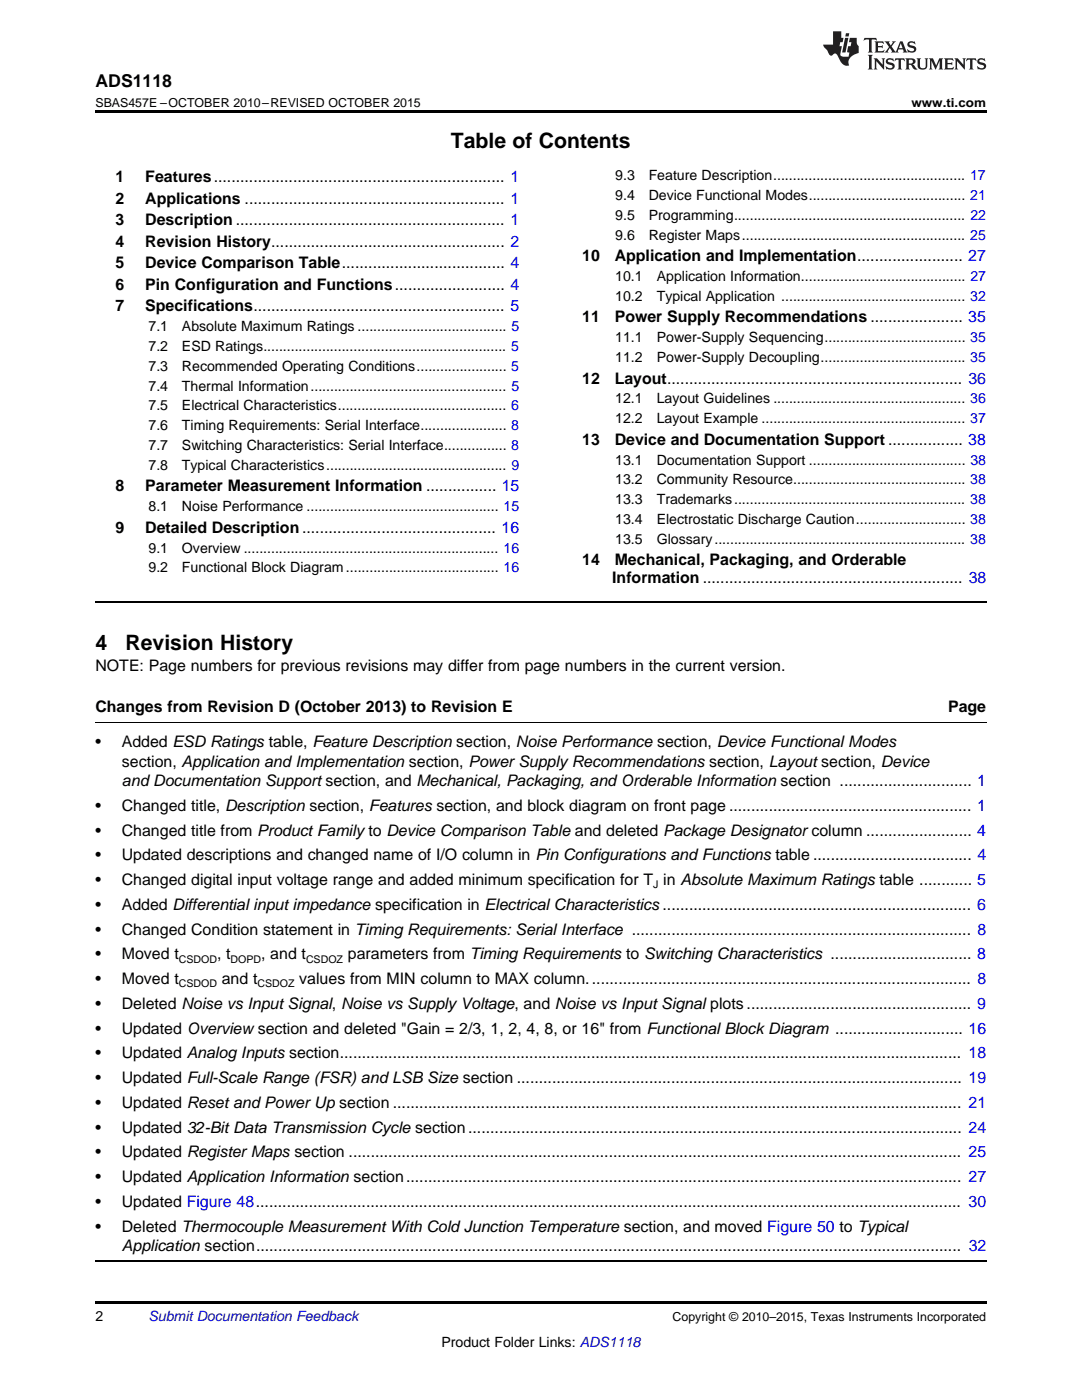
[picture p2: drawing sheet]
<svg xmlns="http://www.w3.org/2000/svg" width="216mm" height="279mm" viewBox="0 0 216 279" stroke-linecap="round" stroke-linejoin="round" font-family="sans-serif">
<defs><g id="words">
<g font-size="4.2">
<text x="90" y="29.6">Table of Contents</text>
<text x="19" y="129.6">4</text>
<text x="25" y="129.6">Revision History</text>
</g>
<text font-size="3.5" x="19" y="17.3">ADS1118</text>
<g font-size="3.2">
<text x="23" y="36.3">1</text>
<text x="23" y="40.6">2</text>
<text x="29" y="36.3">Features.................................................................. 1</text>
<text x="29" y="40.6">Applications ........................................................... 1</text>
<text x="23" y="44.9">3</text>
<text x="29" y="44.9">Description ............................................................. 1</text>
<text x="23" y="49.2">4</text>
<text x="23" y="53.6">5</text>
<text x="29" y="49.2">Revision History..................................................... 2</text>
<text x="29" y="53.6">Device Comparison Table..................................... 4</text>
<text x="116.2" y="52.1">10</text>
<text x="122.7" y="52.1">Application and Implementation........................ 27</text>
<text x="23" y="57.9">6</text>
<text x="29" y="57.9">Pin Configuration and Functions......................... 4</text>
<text x="23" y="62.2">7</text>
<text x="29" y="62.2">Specifications......................................................... 5</text>
<text x="116.2" y="64.3">11</text>
<text x="122.7" y="64.3">Power Supply Recommendations ..................... 35</text>
<text x="116.2" y="76.6">12</text>
<text x="122.7" y="76.6">Layout................................................................... 36</text>
<text x="116.2" y="88.8">13</text>
<text x="122.7" y="88.8">Device and Documentation Support ................. 38</text>
<text x="23" y="98.1">8</text>
<text x="29" y="98.1">Parameter Measurement Information ................ 15</text>
<text x="23" y="106.3">9</text>
<text x="29" y="106.3">Detailed Description............................................ 16</text>
<text x="116.2" y="112.8">14</text>
<text x="122.7" y="112.8">Mechanical, Packaging, and Orderable</text>
<text x="122.2" y="116.3">Information ........................................................... 38</text>
<text x="19" y="133.9">NOTE: Page numbers for previous revisions may differ from page numbers in the current version.</text>
<text x="19" y="142.1">Changes from Revision D (October 2013) to Revision E</text>
<text x="189.2" y="142.1">Page</text>
<text x="19" y="149.1">•</text>
<text x="24.3" y="149.1">Added ESD Ratings table, Feature Description section, Noise Performance section, Device Functional Modes</text>
<text x="24.3" y="153">section, Application and Implementation section, Power Supply Recommendations section, Layout section, Device</text>
<text x="19" y="161.8">•</text>
<text x="24.3" y="161.8">Changed title, Description section, Features section, and block diagram on front page ....................................................... 1</text>
<text x="24.3" y="156.9">and Documentation Support section, and Mechanical, Packaging, and Orderable Information section .............................. 1</text>
<text x="19" y="166.8">•</text>
<text x="24.3" y="166.8">Changed title from Product Family to Device Comparison Table and deleted Package Designator column ........................ 4</text>
<text x="19" y="171.7">•</text>
<text x="24.3" y="171.7">Updated descriptions and changed name of I/O column in Pin Configurations and Functions table .................................... 4</text>
<text x="19" y="176.6">•</text>
<text x="24.3" y="176.6">Changed digital input voltage range and added minimum specification for T in Absolute Maximum Ratings table ............ 5</text>
<text x="19" y="181.6">•</text>
<text x="24.3" y="181.6">Added Differential input impedance specification in Electrical Characteristics ...................................................................... 6</text>
<text x="19" y="186.5">•</text>
<text x="19" y="191.5">•</text>
<text x="24.3" y="186.5">Changed Condition statement in Timing Requirements: Serial Interface ............................................................................. 8</text>
<text x="24.3" y="191.5">Moved t</text>
<text x="43.3" y="191.5">, t</text>
<text x="52.1" y="191.5">, and t</text>
<text x="69.4" y="191.5">parameters from Timing Requirements to Switching Characteristics ................................ 8</text>
<text x="19" y="196.4">•</text>
<text x="24.3" y="196.4">Moved t</text>
<text x="44.2" y="196.4">and t</text>
<text x="59.7" y="196.4">values from MIN column to MAX column....................................................................................... 8</text>
<text x="19" y="201.3">•</text>
<text x="24.3" y="201.3">Deleted Noise vs Input Signal, Noise vs Supply Voltage, and Noise vs Input Signal plots ................................................... 9</text>
<text x="19" y="206.3">•</text>
<text x="24.3" y="206.3">Updated Overview section and deleted &quot;Gain = 2/3, 1, 2, 4, 8, or 16&quot; from Functional Block Diagram ............................. 16</text>
<text x="19" y="211.2">•</text>
<text x="24.3" y="211.2">Updated Analog Inputs section............................................................................................................................................. 18</text>
<text x="19" y="216.1">•</text>
<text x="19" y="221.1">•</text>
<text x="24.3" y="216.1">Updated Full-Scale Range (FSR) and LSB Size section ..................................................................................................... 19</text>
<text x="24.3" y="221.1">Updated Reset and Power Up section ................................................................................................................................. 21</text>
<text x="19" y="226">•</text>
<text x="24.3" y="226">Updated 32-Bit Data Transmission Cycle section................................................................................................................ 24</text>
<text x="19" y="231">•</text>
<text x="24.3" y="231">Updated Register Maps section ........................................................................................................................................... 25</text>
<text x="19" y="235.9">•</text>
<text x="24.3" y="235.9">Updated Application Information section.............................................................................................................................. 27</text>
<text x="19" y="240.8">•</text>
<text x="19" y="245.8">•</text>
<text x="24.3" y="240.8">Updated Figure 48................................................................................................................................................................ 30</text>
<text x="24.3" y="245.8">Deleted Thermocouple Measurement With Cold Junction Temperature section, and moved Figure 50 to Typical</text>
<text x="24.3" y="249.7">Application section................................................................................................................................................................ 32</text>
</g>
<g font-size="2.8">
<text x="122.8" y="36">9.3</text>
<text x="129.4" y="36">Feature Description................................................. 17</text>
<text x="122.8" y="39.9">9.4</text>
<text x="129.4" y="39.9">Device Functional Modes........................................ 21</text>
<text x="122.8" y="43.9">9.5</text>
<text x="122.8" y="47.8">9.6</text>
<text x="129.4" y="43.9">Programming........................................................... 22</text>
<text x="129.4" y="47.8">Register Maps......................................................... 25</text>
<text x="122.8" y="56.1">10.1</text>
<text x="131" y="56.1">Application Information.......................................... 27</text>
<text x="122.8" y="60">10.2</text>
<text x="131" y="60">Typical Application ............................................... 32</text>
<text x="29.6" y="66.1">7.1</text>
<text x="29.6" y="70.1">7.2</text>
<text x="36.3" y="66.1">Absolute Maximum Ratings ...................................... 5</text>
<text x="36.3" y="70.1">ESD Ratings.............................................................. 5</text>
<text x="122.8" y="68.3">11.1</text>
<text x="131" y="68.3">Power-Supply Sequencing.................................... 35</text>
<text x="29.6" y="74">7.3</text>
<text x="29.6" y="78">7.4</text>
<text x="36.3" y="74">Recommended Operating Conditions....................... 5</text>
<text x="36.3" y="78">Thermal Information.................................................. 5</text>
<text x="122.8" y="72.2">11.2</text>
<text x="131" y="72.2">Power-Supply Decoupling..................................... 35</text>
<text x="29.6" y="81.9">7.5</text>
<text x="36.3" y="81.9">Electrical Characteristics........................................... 6</text>
<text x="122.8" y="80.5">12.1</text>
<text x="131" y="80.5">Layout Guidelines ................................................. 36</text>
<text x="29.6" y="85.9">7.6</text>
<text x="29.6" y="89.8">7.7</text>
<text x="36.3" y="85.9">Timing Requirements: Serial Interface...................... 8</text>
<text x="36.3" y="89.8">Switching Characteristics: Serial Interface................ 8</text>
<text x="122.8" y="84.5">12.2</text>
<text x="131" y="84.5">Layout Example .................................................... 37</text>
<text x="29.6" y="93.8">7.8</text>
<text x="36.3" y="93.8">Typical Characteristics.............................................. 9</text>
<text x="122.8" y="92.7">13.1</text>
<text x="131" y="92.7">Documentation Support ........................................ 38</text>
<text x="122.8" y="96.7">13.2</text>
<text x="122.8" y="100.6">13.3</text>
<text x="131" y="96.7">Community Resource............................................ 38</text>
<text x="131" y="100.6">Trademarks........................................................... 38</text>
<text x="29.6" y="102">8.1</text>
<text x="36.3" y="102">Noise Performance ................................................. 15</text>
<text x="122.8" y="104.6">13.4</text>
<text x="131" y="104.6">Electrostatic Discharge Caution............................ 38</text>
<text x="29.6" y="110.3">9.1</text>
<text x="36.3" y="110.3">Overview ................................................................. 16</text>
<text x="122.8" y="108.5">13.5</text>
<text x="131" y="108.5">Glossary................................................................ 38</text>
<text x="29.6" y="114.2">9.2</text>
<text x="36.3" y="114.2">Functional Block Diagram....................................... 16</text>
<text x="19" y="263.6">2</text>
<text x="88.1" y="268.9">Product Folder Links: ADS1118</text>
</g>
<text font-size="2.8" fill="#0000c8" x="29.6" y="263.6">Submit Documentation Feedback</text>
<g font-size="2.5">
<text x="19" y="21.4">SBAS457E –OCTOBER 2010–REVISED OCTOBER 2015</text>
<text x="181.9" y="21.4">www.ti.com</text>
<text x="134.2" y="263.6">Copyright © 2010–2015, Texas Instruments Incorporated</text>
</g>
<g font-size="2.1">
<text x="130.3" y="177.3">J</text>
<text x="35.7" y="192.1">CSDOD</text>
<text x="35.7" y="197">CSDOD</text>
<text x="46" y="192.1">DOPD</text>
<text x="51.4" y="197">CSDOZ</text>
<text x="61.1" y="192.1">CSDOZ</text>
</g>
</g></defs>
<path d="M19 22h177.8v.5h-177.8zM19 259.7h177.8v.5h-177.8z" fill="#000"/>
<path d="M19 120.1h177.8M19 251.6h177.8" fill="none" stroke="#000" stroke-width=".35"/>
<path d="M19 144.1h177.8" fill="none" stroke="#000" stroke-width=".2"/>
<g fill="#231f20">
<path d="M172.5 7.6l-.1 .5 .4-.2h.6v.1v2.1l-.2 .4h.9l-.2-.4v-2.1l.1-.1h.5l.5 .2-.2-.5zM174.5 8.3l.2 .3v1.5l-.2 .4h1.8l.2-.6a1.04 1.04 0 0 1-1.3 .2v-.7h.6l.3 .2v-.6l-.3 .2h-.6v-.6l.8-.1 .4 .3-.2-.5zM176.5 8.3l.9 1.1-.9 1.1h.8l-.2-.2 .4-.7 .5 .7-.2 .2h1.5l-.2-.2 .2-.4h.9l.1 .4-.2 .2h1l-.3-.3-.7-1.9h-.5l-.9 2-.8-1 .9-1h-.8l.1 .3-.4 .5-.3-.6 .1-.2zM179.7 8.6l.4 1h-.7zM181.3 8.4a.63 .63 0 0 0-.2 .7 .63 .63 0 0 0 .6 .4l.6 .2 .1 .2a.75 .75 0 0 1-.7 .4 .75 .75 0 0 1-.6-.5l.1 .7 .1-.1a1.11 1.11 0 0 0 1.5-.6 1.13 1.13 0 0 0-1.2-.8l-.1-.4a1.04 1.04 0 0 1 1.2 .2l-.2-.5-.2 .1-.4-.2zM173.2 10.9l.2 .4v2.2l-.2 .4h1l-.3-.4v-2.2l.3-.4zM174.3 11.6l.3 .4v1.5l-.3 .4h.8l-.2-.4v-1.3l1.5 1.7v-1.9l.2-.4h-.7l.2 .4v.9l-1.1-1.3zM177 11.8a.62 .62 0 0 0-.2 .7 .62 .62 0 0 0 .6 .4l.6 .1 .1 .3a.76 .76 0 0 1-.7 .3 .76 .76 0 0 1-.7-.4l.2 .7 .1-.1a1.11 1.11 0 0 0 1.5-.6 1.13 1.13 0 0 0-1.2-.8l-.1-.4a1.04 1.04 0 0 1 1.2 .2l-.2-.6-.2 .1-.5-.1zM178.7 11.6l-.2 .6a.61 .61 0 0 1 .8-.3v1.6l-.2 .4h.9l-.2-.4v-1.6a.63 .63 0 0 1 .7 .3l-.1-.6zM180.6 11.6l.3 .4v1.5l-.3 .4h1l-.2-.2-.1-.8 .6 .2a.76 .76 0 0 0 1.2 .7l-1-1a.58 .58 0 0 0 .6-.5 .58 .58 0 0 0-.5-.6zM181.4 11.9h.1a.45 .45 0 0 1 .5 .1 .45 .45 0 0 1 .1 .5l-.8 .2zM182.9 11.6l.2 .2a2.17 2.17 0 0 0 .3 1.9 .99 .99 0 0 0 1.6-.6v-1.1l.2-.4h-.7l.2 .2a1.92 1.92 0 0 1-.2 1.8 .6 .6 0 0 1-.9-.5v-1.1l.2-.4zM185.4 11.6l.2 .4v1.5l-.2 .4h.7l-.2-.4v-1.4l.8 1.8 .8-1.8v1.4l-.2 .4h.9l-.2-.4v-1.5l.2-.4h-.8l-.6 1.5-.6-1.5zM188.4 11.6l.2 .4v1.5l-.2 .4h1.8l.1-.6a1.04 1.04 0 0 1-1.2 .1v-.6h.5l.4 .2v-.6l-.4 .2h-.5v-.7h.8l.3 .3-.1-.6zM190.5 11.6l.2 .4v1.5l-.2 .4h.7l-.2-.4v-1.3l1.5 1.7v-1.9l.2-.4h-.7l.2 .4v.9l-1.1-1.3zM192.9 11.6l-.1 .6a.61 .61 0 0 1 .7-.3l.1 1.6-.3 .4h1l-.3-.4 .1-1.6a.63 .63 0 0 1 .7 .3l-.1-.6zM195.2 11.8a.62 .62 0 0 0-.2 .7 .62 .62 0 0 0 .6 .4l.6 .1 .1 .3a.76 .76 0 0 1-.7 .3 .76 .76 0 0 1-.6-.4l.1 .7 .1-.1a1.11 1.11 0 0 0 1.6-.6 1.13 1.13 0 0 0-1.3-.8l-.1-.4a1.04 1.04 0 0 1 1.2 .2l-.1-.6-.2 .1-.5-.1z"/>
<path d="M166.2 6.3v2.6h-1.9v.4l.8 .9a.91 .91 0 0 0 1 .8 .56 .56 0 0 1 .5-.3 .56 .56 0 0 1 .5 .3l.4 .8a1.53 1.53 0 0 0 1.9 1.2 1.54 1.54 0 0 1 1-2.1l.9-.3v-1.4a1.52 1.52 0 0 1-.4-1.6h-1.3l-.2 .8h.5l-.2 .8h-.5l-.1 1v.2l.4 .1-.2 .8a1.93 1.93 0 0 1-1.6-.3l.3-1.8h-.5l.2-.8h.4l.2-.8h-.4v-1.3zM168.6 7.6l-.6 2.9h.7l.6-2.9zM168.8 6.6l-.1 .7h.6l.2-.7z"/>
</g>
<use href="#words"/>
</svg>
